VERSION 5.7 ;
  NOWIREEXTENSIONATPIN ON ;
  DIVIDERCHAR "/" ;
  BUSBITCHARS "[]" ;
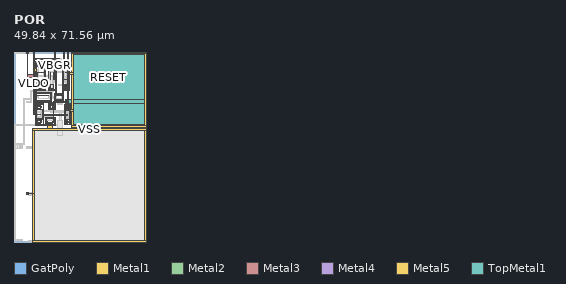
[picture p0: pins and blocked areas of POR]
MACRO POR
  CLASS BLOCK ;
  FOREIGN POR ;
  ORIGIN -315.320 62.220 ;
  SIZE 49.840 BY 71.560 ;
  PIN VLDO
    ANTENNAGATEAREA 5.000000 ;
    ANTENNADIFFAREA 31.500000 ;
    PORT
      LAYER GatPoly ;
        RECT 320.170 8.760 320.670 9.190 ;
        RECT 331.975 6.280 332.475 6.710 ;
        RECT 324.205 3.790 324.385 4.790 ;
        RECT 326.385 4.780 326.565 4.790 ;
        RECT 326.385 3.800 326.755 4.780 ;
        RECT 326.385 3.790 326.565 3.800 ;
        RECT 324.205 -4.130 324.385 -3.130 ;
        RECT 326.385 -3.140 326.565 -3.130 ;
        RECT 326.385 -4.120 326.755 -3.140 ;
        RECT 326.385 -4.130 326.565 -4.120 ;
        RECT 324.160 -11.325 324.340 -11.220 ;
        RECT 323.930 -11.625 324.340 -11.325 ;
        RECT 324.160 -11.720 324.340 -11.625 ;
        RECT 325.340 -11.720 325.520 -11.220 ;
        RECT 324.160 -16.745 324.340 -16.640 ;
        RECT 323.930 -17.045 324.340 -16.745 ;
        RECT 324.160 -17.140 324.340 -17.045 ;
        RECT 325.340 -17.140 325.520 -16.640 ;
      LAYER Metal1 ;
        RECT 320.190 8.910 320.650 9.170 ;
        RECT 331.995 6.665 332.455 6.690 ;
        RECT 331.755 6.455 332.455 6.665 ;
        RECT 331.995 6.430 332.455 6.455 ;
        RECT 323.515 5.590 327.265 5.890 ;
        RECT 323.515 3.130 323.815 5.590 ;
        RECT 324.385 5.060 326.385 5.590 ;
        RECT 324.385 4.900 326.685 5.060 ;
        RECT 326.525 3.680 326.685 4.900 ;
        RECT 324.385 3.520 326.685 3.680 ;
        RECT 322.755 2.020 323.815 3.130 ;
        RECT 320.310 -0.200 320.520 0.910 ;
        RECT 322.755 -0.200 322.965 0.910 ;
        RECT 323.515 -4.910 323.815 2.020 ;
        RECT 324.045 1.630 326.385 1.790 ;
        RECT 324.045 0.910 324.205 1.630 ;
        RECT 323.995 -0.200 324.205 0.910 ;
        RECT 324.045 -0.970 324.205 -0.200 ;
        RECT 324.045 -1.130 326.385 -0.970 ;
        RECT 324.385 -3.020 326.685 -2.860 ;
        RECT 326.525 -4.240 326.685 -3.020 ;
        RECT 324.385 -4.400 326.685 -4.240 ;
        RECT 324.385 -4.910 326.385 -4.400 ;
        RECT 326.965 -4.910 327.265 5.590 ;
        RECT 323.515 -5.210 327.265 -4.910 ;
        RECT 323.515 -5.910 323.815 -5.210 ;
        RECT 323.515 -6.210 329.365 -5.910 ;
        RECT 323.515 -8.960 323.815 -6.210 ;
        RECT 324.435 -6.905 328.005 -6.880 ;
        RECT 324.435 -7.065 328.435 -6.905 ;
        RECT 324.435 -7.090 328.005 -7.065 ;
        RECT 329.065 -8.960 329.365 -6.210 ;
        RECT 323.515 -9.260 329.365 -8.960 ;
        RECT 323.515 -9.960 323.815 -9.260 ;
        RECT 323.515 -10.260 326.565 -9.960 ;
        RECT 323.515 -18.110 323.815 -10.260 ;
        RECT 324.340 -10.950 325.340 -10.260 ;
        RECT 324.000 -11.110 325.340 -10.950 ;
        RECT 324.000 -11.830 324.160 -11.110 ;
        RECT 324.000 -11.990 325.340 -11.830 ;
        RECT 324.435 -14.100 325.135 -14.075 ;
        RECT 324.340 -14.260 325.340 -14.100 ;
        RECT 324.435 -14.285 325.135 -14.260 ;
        RECT 324.000 -16.530 325.340 -16.370 ;
        RECT 324.000 -17.250 324.160 -16.530 ;
        RECT 324.000 -17.410 325.340 -17.250 ;
        RECT 324.340 -18.110 325.340 -17.410 ;
        RECT 326.265 -18.110 326.565 -10.260 ;
        RECT 329.070 -10.705 329.770 -10.680 ;
        RECT 328.925 -10.865 329.925 -10.705 ;
        RECT 329.070 -10.890 329.770 -10.865 ;
        RECT 327.225 -15.760 330.825 -15.460 ;
        RECT 327.225 -18.110 327.525 -15.760 ;
        RECT 330.525 -18.110 330.825 -15.760 ;
        RECT 323.515 -18.410 330.825 -18.110 ;
      LAYER Metal2 ;
        RECT 320.270 -0.200 320.560 9.140 ;
        RECT 322.490 -14.280 322.985 9.340 ;
        RECT 331.755 6.455 332.455 6.665 ;
        RECT 324.000 -0.200 324.200 0.910 ;
        RECT 324.435 -7.085 328.005 -6.885 ;
        RECT 329.070 -10.885 329.770 -9.525 ;
        RECT 324.340 -14.280 325.190 -14.080 ;
      LAYER Metal3 ;
        RECT 322.490 6.415 332.455 6.705 ;
        RECT 322.760 2.020 322.960 3.130 ;
        RECT 320.315 -0.200 324.200 0.910 ;
        RECT 322.490 -7.085 328.005 -6.885 ;
        RECT 322.490 -9.725 329.770 -9.525 ;
        RECT 322.490 -14.280 325.135 -14.080 ;
    END
  END VLDO
  PIN RESET
    ANTENNAGATEAREA 1.500000 ;
    ANTENNADIFFAREA 0.870000 ;
    PORT
      LAYER GatPoly ;
        RECT 328.745 -11.475 328.925 -10.975 ;
        RECT 329.925 -11.070 330.105 -10.975 ;
        RECT 329.925 -11.370 330.360 -11.070 ;
        RECT 329.925 -11.475 330.105 -11.370 ;
        RECT 327.745 -17.185 327.925 -16.685 ;
        RECT 329.925 -16.800 330.105 -16.685 ;
        RECT 329.925 -17.100 330.360 -16.800 ;
        RECT 329.925 -17.185 330.105 -17.100 ;
      LAYER Metal1 ;
        RECT 330.105 -11.475 330.315 -10.975 ;
        RECT 324.340 -12.500 326.035 -12.340 ;
        RECT 325.875 -14.120 326.035 -12.500 ;
        RECT 325.875 -14.410 326.085 -14.120 ;
        RECT 335.190 -14.160 335.400 -14.120 ;
        RECT 335.120 -14.370 335.620 -14.160 ;
        RECT 335.190 -14.410 335.400 -14.370 ;
        RECT 325.875 -15.860 326.035 -14.410 ;
        RECT 324.340 -16.020 326.035 -15.860 ;
        RECT 330.105 -17.185 330.315 -16.685 ;
      LAYER Metal2 ;
        RECT 335.345 -9.045 335.840 9.340 ;
        RECT 325.875 -14.610 326.155 -13.920 ;
        RECT 330.105 -17.185 330.310 -9.440 ;
        RECT 335.275 -9.745 335.885 -9.045 ;
        RECT 335.195 -14.160 335.395 -14.120 ;
        RECT 334.900 -14.370 335.590 -14.160 ;
        RECT 335.195 -14.410 335.395 -14.370 ;
      LAYER Metal3 ;
        RECT 335.275 -9.440 335.885 -9.045 ;
        RECT 330.110 -9.730 335.885 -9.440 ;
        RECT 335.275 -9.745 335.885 -9.730 ;
        RECT 325.880 -14.410 335.400 -14.120 ;
      LAYER Metal4 ;
        RECT 335.275 -9.745 335.885 -9.045 ;
      LAYER Metal5 ;
        RECT 335.270 -9.745 335.890 -9.045 ;
      LAYER TopMetal1 ;
        RECT 337.840 -8.575 364.300 8.390 ;
        RECT 334.760 -10.215 364.300 -8.575 ;
        RECT 337.840 -18.070 364.300 -10.215 ;
    END
  END RESET
  PIN VBGR
    ANTENNAGATEAREA 2.000000 ;
    PORT
      LAYER GatPoly ;
        RECT 328.880 0.520 329.060 1.520 ;
        RECT 330.060 1.340 330.580 1.520 ;
        RECT 330.060 0.700 330.880 1.340 ;
        RECT 330.060 0.520 330.580 0.700 ;
        RECT 328.880 -0.860 329.060 0.140 ;
        RECT 330.060 -0.040 330.580 0.140 ;
        RECT 330.060 -0.680 330.880 -0.040 ;
        RECT 330.060 -0.860 330.580 -0.680 ;
      LAYER Metal1 ;
        RECT 330.625 0.670 330.835 1.370 ;
        RECT 330.625 -0.710 330.835 -0.010 ;
      LAYER Metal2 ;
        RECT 330.630 -0.710 330.830 9.340 ;
    END
  END VBGR
  PIN VSS
    USE GROUND ;
    PORT
      LAYER GatPoly ;
        RECT 328.880 4.780 329.060 4.790 ;
        RECT 328.650 3.800 329.060 4.780 ;
        RECT 328.880 3.790 329.060 3.800 ;
        RECT 330.060 3.790 330.240 4.790 ;
        RECT 334.455 4.780 334.635 4.790 ;
        RECT 334.195 3.800 334.635 4.780 ;
        RECT 334.455 3.790 334.635 3.800 ;
        RECT 335.135 3.790 335.315 4.790 ;
        RECT 328.880 -3.140 329.060 -3.130 ;
        RECT 328.650 -4.120 329.060 -3.140 ;
        RECT 328.880 -4.130 329.060 -4.120 ;
        RECT 330.060 -4.130 330.240 -3.130 ;
        RECT 334.455 -3.140 334.635 -3.130 ;
        RECT 334.195 -4.120 334.635 -3.140 ;
        RECT 334.455 -4.130 334.635 -4.120 ;
        RECT 335.135 -4.130 335.315 -3.130 ;
        RECT 334.940 -11.400 335.120 -11.305 ;
        RECT 334.710 -11.700 335.120 -11.400 ;
        RECT 334.940 -11.805 335.120 -11.700 ;
        RECT 335.620 -11.805 335.800 -11.305 ;
        RECT 334.940 -16.820 335.120 -16.725 ;
        RECT 334.710 -17.120 335.120 -16.820 ;
        RECT 334.940 -17.225 335.120 -17.120 ;
        RECT 335.620 -17.225 335.800 -16.725 ;
        RECT 320.170 -44.190 320.670 -43.760 ;
      LAYER Metal1 ;
        RECT 333.935 5.670 334.430 9.340 ;
        RECT 328.160 5.360 331.360 5.660 ;
        RECT 328.160 -4.740 328.460 5.360 ;
        RECT 329.060 5.060 330.060 5.360 ;
        RECT 328.720 4.900 330.060 5.060 ;
        RECT 328.720 3.680 328.880 4.900 ;
        RECT 328.720 3.520 330.060 3.680 ;
        RECT 328.720 -3.020 330.060 -2.860 ;
        RECT 328.720 -4.240 328.880 -3.020 ;
        RECT 328.720 -4.400 330.060 -4.240 ;
        RECT 329.060 -4.740 330.060 -4.400 ;
        RECT 331.060 -4.740 331.360 5.360 ;
        RECT 328.160 -5.040 331.360 -4.740 ;
        RECT 333.695 5.370 336.295 5.670 ;
        RECT 333.695 -0.970 333.995 5.370 ;
        RECT 334.630 5.060 335.135 5.370 ;
        RECT 334.240 4.900 335.135 5.060 ;
        RECT 334.240 3.680 334.450 4.900 ;
        RECT 334.240 3.520 335.135 3.680 ;
        RECT 334.635 1.630 335.475 1.790 ;
        RECT 335.315 -0.970 335.475 1.630 ;
        RECT 333.695 -1.130 335.475 -0.970 ;
        RECT 333.695 -4.730 333.995 -1.130 ;
        RECT 334.240 -3.020 335.135 -2.860 ;
        RECT 334.240 -4.240 334.450 -3.020 ;
        RECT 334.240 -4.400 335.135 -4.240 ;
        RECT 334.630 -4.730 335.135 -4.400 ;
        RECT 335.995 -4.730 336.295 5.370 ;
        RECT 333.695 -5.030 336.295 -4.730 ;
        RECT 331.060 -6.315 331.365 -5.040 ;
        RECT 333.695 -6.315 334.000 -5.030 ;
        RECT 330.505 -6.615 334.005 -6.315 ;
        RECT 330.505 -8.615 330.805 -6.615 ;
        RECT 331.375 -7.080 333.375 -6.615 ;
        RECT 333.705 -8.615 334.005 -6.615 ;
        RECT 330.505 -8.915 334.005 -8.615 ;
        RECT 330.510 -10.060 330.805 -8.915 ;
        RECT 328.210 -10.360 330.810 -10.060 ;
        RECT 328.210 -12.060 328.510 -10.360 ;
        RECT 330.510 -12.060 330.810 -10.360 ;
        RECT 328.210 -12.360 330.810 -12.060 ;
        RECT 334.290 -10.715 336.540 -10.415 ;
        RECT 327.965 -17.295 329.895 -17.270 ;
        RECT 327.925 -17.455 329.925 -17.295 ;
        RECT 327.965 -17.480 329.895 -17.455 ;
        RECT 334.290 -17.815 334.590 -10.715 ;
        RECT 335.120 -11.035 335.620 -10.715 ;
        RECT 334.775 -11.195 335.620 -11.035 ;
        RECT 334.775 -11.915 334.940 -11.195 ;
        RECT 334.775 -12.075 335.620 -11.915 ;
        RECT 336.240 -12.425 336.540 -10.715 ;
        RECT 335.120 -12.585 336.540 -12.425 ;
        RECT 336.240 -15.945 336.540 -12.585 ;
        RECT 335.120 -16.105 336.540 -15.945 ;
        RECT 334.775 -16.615 335.620 -16.455 ;
        RECT 334.775 -17.335 334.940 -16.615 ;
        RECT 334.775 -17.495 335.620 -17.335 ;
        RECT 335.120 -17.815 335.620 -17.495 ;
        RECT 336.240 -17.815 336.540 -16.105 ;
        RECT 334.290 -18.115 336.540 -17.815 ;
        RECT 320.190 -43.930 320.650 -43.910 ;
        RECT 319.950 -44.140 320.650 -43.930 ;
        RECT 320.190 -44.170 320.650 -44.140 ;
      LAYER Metal2 ;
        RECT 336.055 0.920 336.265 1.620 ;
        RECT 336.305 -13.120 336.515 -12.420 ;
        RECT 327.965 -17.475 329.895 -17.275 ;
        RECT 319.950 -44.140 320.650 -43.930 ;
      LAYER Metal3 ;
        RECT 336.055 0.920 336.265 1.620 ;
        RECT 336.305 -13.120 336.515 -12.420 ;
        RECT 327.965 -17.475 329.895 -17.275 ;
        RECT 319.950 -44.140 320.650 -43.930 ;
      LAYER Metal4 ;
        RECT 336.055 0.920 336.265 1.620 ;
        RECT 336.305 -13.120 336.515 -12.420 ;
        RECT 327.965 -17.475 329.895 -17.275 ;
        RECT 319.950 -44.140 320.650 -43.930 ;
      LAYER Metal5 ;
        RECT 336.980 8.650 365.160 9.250 ;
        RECT 336.980 1.620 337.580 8.650 ;
        RECT 336.040 0.920 337.580 1.620 ;
        RECT 336.980 -12.420 337.580 0.920 ;
        RECT 336.290 -13.120 337.580 -12.420 ;
        RECT 327.965 -19.500 329.895 -17.275 ;
        RECT 336.980 -18.330 337.580 -13.120 ;
        RECT 364.560 -18.330 365.160 8.650 ;
        RECT 336.980 -18.930 365.160 -18.330 ;
        RECT 336.980 -19.500 337.570 -18.930 ;
        RECT 322.440 -20.100 365.160 -19.500 ;
        RECT 322.440 -43.930 323.040 -20.100 ;
        RECT 319.950 -44.140 323.040 -43.930 ;
        RECT 322.440 -61.620 323.040 -44.140 ;
        RECT 364.560 -61.620 365.160 -20.100 ;
        RECT 322.440 -62.220 365.160 -61.620 ;
    END
  END VSS
  OBS
      LAYER GatPoly ;
        RECT 315.350 8.760 315.850 9.190 ;
        RECT 316.030 8.760 316.530 9.190 ;
        RECT 316.745 8.760 317.245 9.190 ;
        RECT 317.445 8.760 317.945 9.190 ;
        RECT 318.145 8.760 318.645 9.190 ;
        RECT 318.850 8.760 319.350 9.190 ;
        RECT 320.870 8.760 321.370 9.190 ;
        RECT 321.570 8.760 322.070 9.190 ;
        RECT 332.655 6.280 333.155 6.710 ;
        RECT 324.205 1.900 324.385 2.900 ;
        RECT 326.385 2.890 326.565 2.900 ;
        RECT 326.385 1.910 326.795 2.890 ;
        RECT 326.385 1.900 326.565 1.910 ;
        RECT 328.880 1.900 329.060 2.900 ;
        RECT 330.060 2.710 330.240 2.900 ;
        RECT 330.060 2.070 330.435 2.710 ;
        RECT 330.060 1.900 330.240 2.070 ;
        RECT 334.455 1.900 334.635 2.900 ;
        RECT 335.135 2.890 335.585 2.900 ;
        RECT 335.135 1.910 335.885 2.890 ;
        RECT 335.135 1.900 335.585 1.910 ;
        RECT 324.205 0.520 324.385 1.520 ;
        RECT 326.385 1.510 326.565 1.520 ;
        RECT 326.385 0.530 326.795 1.510 ;
        RECT 326.385 0.520 326.565 0.530 ;
        RECT 334.455 0.520 334.635 1.520 ;
        RECT 335.135 1.510 335.585 1.520 ;
        RECT 335.135 0.530 335.885 1.510 ;
        RECT 335.135 0.520 335.585 0.530 ;
        RECT 324.205 -0.860 324.385 0.140 ;
        RECT 326.385 0.130 326.565 0.140 ;
        RECT 326.385 -0.850 326.795 0.130 ;
        RECT 326.385 -0.860 326.565 -0.850 ;
        RECT 334.455 -0.860 334.635 0.140 ;
        RECT 335.135 0.130 335.585 0.140 ;
        RECT 335.135 -0.850 335.885 0.130 ;
        RECT 335.135 -0.860 335.585 -0.850 ;
        RECT 324.205 -2.240 324.385 -1.240 ;
        RECT 326.385 -1.250 326.565 -1.240 ;
        RECT 326.385 -2.230 326.795 -1.250 ;
        RECT 326.385 -2.240 326.565 -2.230 ;
        RECT 328.880 -2.240 329.060 -1.240 ;
        RECT 330.060 -1.420 330.240 -1.240 ;
        RECT 330.060 -2.060 330.435 -1.420 ;
        RECT 330.060 -2.240 330.240 -2.060 ;
        RECT 334.455 -2.240 334.635 -1.240 ;
        RECT 335.135 -1.250 335.585 -1.240 ;
        RECT 335.135 -2.230 335.885 -1.250 ;
        RECT 335.135 -2.240 335.585 -2.230 ;
        RECT 331.975 -3.150 332.475 -2.720 ;
        RECT 332.655 -3.150 333.155 -2.720 ;
        RECT 324.255 -7.975 324.435 -7.175 ;
        RECT 328.435 -7.390 328.615 -7.175 ;
        RECT 331.195 -7.390 331.375 -7.190 ;
        RECT 328.435 -7.690 328.805 -7.390 ;
        RECT 330.945 -7.690 331.375 -7.390 ;
        RECT 328.435 -7.975 328.615 -7.690 ;
        RECT 331.195 -7.990 331.375 -7.690 ;
        RECT 333.375 -7.990 333.555 -7.190 ;
        RECT 320.170 -8.470 320.670 -8.040 ;
        RECT 320.870 -8.470 321.370 -8.040 ;
        RECT 321.570 -8.470 322.070 -8.040 ;
        RECT 320.170 -9.600 320.670 -9.170 ;
        RECT 320.870 -9.600 321.370 -9.170 ;
        RECT 321.570 -9.600 322.070 -9.170 ;
        RECT 331.655 -10.460 333.655 -10.030 ;
        RECT 324.160 -13.110 324.340 -12.610 ;
        RECT 325.340 -12.715 325.520 -12.610 ;
        RECT 334.940 -12.715 335.120 -12.695 ;
        RECT 325.340 -13.015 325.715 -12.715 ;
        RECT 334.735 -13.015 335.120 -12.715 ;
        RECT 325.340 -13.110 325.520 -13.015 ;
        RECT 334.940 -13.195 335.120 -13.015 ;
        RECT 335.620 -13.195 335.800 -12.695 ;
        RECT 324.160 -13.990 324.340 -13.490 ;
        RECT 325.340 -13.585 325.520 -13.490 ;
        RECT 325.340 -13.885 325.715 -13.585 ;
        RECT 334.940 -13.675 335.120 -13.575 ;
        RECT 325.340 -13.990 325.520 -13.885 ;
        RECT 334.710 -13.975 335.120 -13.675 ;
        RECT 334.940 -14.075 335.120 -13.975 ;
        RECT 335.620 -14.075 335.800 -13.575 ;
        RECT 324.160 -14.870 324.340 -14.370 ;
        RECT 325.340 -14.465 325.520 -14.370 ;
        RECT 325.340 -14.765 325.715 -14.465 ;
        RECT 334.940 -14.555 335.120 -14.455 ;
        RECT 325.340 -14.870 325.520 -14.765 ;
        RECT 334.710 -14.855 335.120 -14.555 ;
        RECT 334.940 -14.955 335.120 -14.855 ;
        RECT 335.620 -14.955 335.800 -14.455 ;
        RECT 324.160 -15.750 324.340 -15.250 ;
        RECT 325.340 -15.345 325.520 -15.250 ;
        RECT 325.340 -15.645 325.715 -15.345 ;
        RECT 334.940 -15.435 335.120 -15.335 ;
        RECT 325.340 -15.750 325.520 -15.645 ;
        RECT 334.710 -15.735 335.120 -15.435 ;
        RECT 334.940 -15.835 335.120 -15.735 ;
        RECT 335.620 -15.835 335.800 -15.335 ;
        RECT 331.655 -18.340 333.655 -17.910 ;
        RECT 315.350 -25.670 315.850 -25.240 ;
        RECT 316.030 -25.670 316.530 -25.240 ;
        RECT 316.745 -25.670 317.245 -25.240 ;
        RECT 317.445 -25.670 317.945 -25.240 ;
        RECT 318.145 -25.670 318.645 -25.240 ;
        RECT 318.850 -25.670 319.350 -25.240 ;
        RECT 315.350 -27.100 315.850 -26.670 ;
        RECT 316.030 -27.100 316.530 -26.670 ;
        RECT 316.745 -27.100 317.245 -26.670 ;
        RECT 317.445 -27.100 317.945 -26.670 ;
        RECT 318.145 -27.100 318.645 -26.670 ;
        RECT 320.170 -26.960 320.670 -26.400 ;
        RECT 320.870 -26.960 321.370 -26.400 ;
        RECT 321.570 -26.960 322.070 -26.400 ;
        RECT 320.870 -44.190 321.370 -43.760 ;
        RECT 321.570 -44.190 322.070 -43.760 ;
        RECT 320.870 -44.800 321.370 -44.370 ;
        RECT 321.570 -44.800 322.070 -44.370 ;
        RECT 315.350 -61.530 315.850 -61.100 ;
        RECT 316.030 -61.530 316.530 -61.100 ;
        RECT 316.745 -61.530 317.245 -61.100 ;
        RECT 317.445 -61.530 317.945 -61.100 ;
        RECT 318.145 -61.530 318.645 -61.100 ;
        RECT 320.870 -62.030 321.370 -61.600 ;
        RECT 321.570 -62.030 322.070 -61.600 ;
      LAYER Metal1 ;
        RECT 315.370 8.910 316.510 9.170 ;
        RECT 316.765 8.910 317.925 9.170 ;
        RECT 318.165 8.910 319.330 9.170 ;
        RECT 320.890 8.910 322.050 9.170 ;
        RECT 332.675 6.430 333.135 6.690 ;
        RECT 324.455 3.170 326.385 3.195 ;
        RECT 329.150 3.170 329.850 3.195 ;
        RECT 334.435 3.170 335.135 3.195 ;
        RECT 324.385 3.010 326.725 3.170 ;
        RECT 324.455 2.985 326.385 3.010 ;
        RECT 324.455 0.410 326.385 0.435 ;
        RECT 324.385 0.250 326.385 0.410 ;
        RECT 324.455 0.225 326.385 0.250 ;
        RECT 326.565 -2.350 326.725 3.010 ;
        RECT 324.385 -2.510 326.725 -2.350 ;
        RECT 328.720 3.010 330.060 3.170 ;
        RECT 334.435 3.010 335.815 3.170 ;
        RECT 328.720 -2.350 328.880 3.010 ;
        RECT 329.150 2.985 329.850 3.010 ;
        RECT 334.435 2.985 335.135 3.010 ;
        RECT 330.180 2.040 330.390 2.740 ;
        RECT 329.150 1.790 329.850 1.815 ;
        RECT 329.060 1.630 330.435 1.790 ;
        RECT 329.150 1.605 329.850 1.630 ;
        RECT 329.150 0.410 329.850 0.435 ;
        RECT 329.060 0.250 330.060 0.410 ;
        RECT 329.150 0.225 329.850 0.250 ;
        RECT 330.275 -0.970 330.435 1.630 ;
        RECT 334.435 0.225 335.135 0.435 ;
        RECT 329.060 -1.130 330.435 -0.970 ;
        RECT 330.180 -2.090 330.390 -1.390 ;
        RECT 335.655 -2.350 335.815 3.010 ;
        RECT 328.720 -2.510 330.060 -2.350 ;
        RECT 334.635 -2.510 335.815 -2.350 ;
        RECT 331.995 -3.130 333.135 -2.870 ;
        RECT 328.505 -7.690 328.805 -7.390 ;
        RECT 330.990 -7.720 331.245 -7.360 ;
        RECT 324.435 -8.085 328.005 -8.075 ;
        RECT 320.190 -8.450 321.350 -8.190 ;
        RECT 320.190 -9.450 321.350 -9.190 ;
        RECT 321.590 -9.450 322.050 -8.190 ;
        RECT 324.435 -8.245 328.435 -8.085 ;
        RECT 331.645 -8.100 333.165 -8.075 ;
        RECT 324.435 -8.285 328.005 -8.245 ;
        RECT 331.375 -8.260 333.375 -8.100 ;
        RECT 331.645 -8.285 333.165 -8.260 ;
        RECT 331.675 -10.330 333.635 -10.030 ;
        RECT 329.075 -11.585 329.775 -11.570 ;
        RECT 328.925 -11.745 329.925 -11.585 ;
        RECT 329.075 -11.780 329.775 -11.745 ;
        RECT 325.440 -13.050 325.695 -12.680 ;
        RECT 334.780 -13.010 334.990 -12.720 ;
        RECT 324.000 -13.380 325.340 -13.220 ;
        RECT 324.000 -14.980 324.160 -13.380 ;
        RECT 325.440 -13.920 325.695 -13.550 ;
        RECT 325.440 -14.800 325.695 -14.430 ;
        RECT 324.435 -14.980 325.135 -14.955 ;
        RECT 324.000 -15.140 325.340 -14.980 ;
        RECT 324.435 -15.165 325.135 -15.140 ;
        RECT 325.440 -15.680 325.695 -15.310 ;
        RECT 334.780 -15.715 334.940 -13.010 ;
        RECT 335.190 -13.280 335.400 -13.240 ;
        RECT 335.120 -13.305 335.620 -13.280 ;
        RECT 335.120 -13.465 335.960 -13.305 ;
        RECT 335.120 -13.490 335.620 -13.465 ;
        RECT 335.190 -13.530 335.400 -13.490 ;
        RECT 335.800 -15.065 335.960 -13.465 ;
        RECT 335.120 -15.225 335.960 -15.065 ;
        RECT 328.170 -16.415 329.690 -16.390 ;
        RECT 327.925 -16.575 329.925 -16.415 ;
        RECT 328.170 -16.600 329.690 -16.575 ;
        RECT 331.675 -18.340 333.635 -18.040 ;
        RECT 315.370 -26.950 315.830 -25.390 ;
        RECT 316.050 -26.950 316.510 -25.390 ;
        RECT 316.765 -26.950 317.225 -25.390 ;
        RECT 317.465 -26.950 317.925 -25.390 ;
        RECT 318.165 -26.950 318.625 -25.390 ;
        RECT 318.870 -25.650 319.330 -25.390 ;
        RECT 320.190 -26.810 320.650 -26.550 ;
        RECT 320.890 -26.810 321.350 -26.550 ;
        RECT 321.590 -26.810 322.050 -26.550 ;
        RECT 320.890 -44.650 321.350 -43.910 ;
        RECT 321.590 -44.650 322.050 -43.910 ;
        RECT 315.370 -61.510 315.830 -61.250 ;
        RECT 316.050 -61.510 317.230 -61.250 ;
        RECT 317.465 -61.510 318.630 -61.250 ;
        RECT 320.890 -61.905 322.050 -61.645 ;
        RECT 320.890 -62.010 321.350 -61.905 ;
        RECT 321.590 -62.010 322.050 -61.905 ;
      LAYER Metal2 ;
        RECT 324.455 2.990 326.385 3.190 ;
        RECT 329.060 2.990 329.850 3.190 ;
        RECT 332.745 2.990 333.035 6.660 ;
        RECT 334.435 2.985 335.135 3.195 ;
        RECT 329.150 1.605 329.850 1.815 ;
        RECT 324.455 0.230 326.385 0.430 ;
        RECT 329.060 0.230 329.850 0.430 ;
        RECT 321.675 -8.220 321.965 -5.280 ;
        RECT 328.550 -7.925 328.760 -7.225 ;
        RECT 329.150 -7.595 329.850 0.230 ;
        RECT 330.185 -5.570 330.385 2.740 ;
        RECT 334.435 0.225 335.135 1.810 ;
        RECT 330.990 -7.945 331.200 -7.245 ;
        RECT 331.675 -8.080 333.190 -8.075 ;
        RECT 319.005 -8.420 321.965 -8.220 ;
        RECT 324.435 -8.280 328.005 -8.080 ;
        RECT 331.645 -8.280 333.190 -8.080 ;
        RECT 315.455 -61.485 315.745 -18.025 ;
        RECT 319.005 -25.620 319.295 -8.420 ;
        RECT 331.675 -10.080 333.190 -8.280 ;
        RECT 331.675 -10.280 333.620 -10.080 ;
        RECT 324.340 -15.160 325.190 -14.960 ;
        RECT 325.465 -15.640 325.665 -12.710 ;
        RECT 329.075 -13.530 329.775 -11.575 ;
        RECT 328.015 -14.965 329.845 -14.960 ;
        RECT 327.965 -15.165 329.895 -14.965 ;
        RECT 328.015 -16.595 329.845 -15.165 ;
        RECT 332.330 -17.335 333.040 -12.765 ;
        RECT 334.415 -13.010 334.985 -12.720 ;
        RECT 335.195 -13.280 335.395 -13.240 ;
        RECT 334.900 -13.490 335.590 -13.280 ;
        RECT 335.195 -13.530 335.395 -13.490 ;
        RECT 332.135 -17.535 333.245 -17.335 ;
        RECT 332.330 -18.085 333.040 -17.535 ;
        RECT 332.325 -18.280 333.040 -18.085 ;
        RECT 332.325 -18.285 333.025 -18.280 ;
      LAYER Metal3 ;
        RECT 324.455 2.990 329.850 3.190 ;
        RECT 332.745 2.990 335.135 3.190 ;
        RECT 329.150 1.610 335.135 1.810 ;
        RECT 324.455 0.230 329.850 0.430 ;
        RECT 321.715 -5.570 330.385 -5.280 ;
        RECT 328.550 -7.690 331.195 -7.390 ;
        RECT 324.435 -8.280 333.190 -8.080 ;
        RECT 325.465 -13.010 334.985 -12.720 ;
        RECT 329.075 -13.530 335.395 -13.240 ;
        RECT 324.435 -15.160 329.895 -14.960 ;
        RECT 327.965 -15.165 329.895 -15.160 ;
        RECT 332.135 -17.535 333.245 -17.335 ;
        RECT 315.495 -18.090 315.695 -18.045 ;
        RECT 332.330 -18.085 333.030 -18.030 ;
        RECT 332.325 -18.090 333.030 -18.085 ;
        RECT 315.320 -18.290 333.400 -18.090 ;
        RECT 315.495 -18.335 315.695 -18.290 ;
      LAYER Metal4 ;
        RECT 332.135 -17.535 333.245 -17.335 ;
      LAYER Metal5 ;
        RECT 332.135 -17.745 333.245 -17.125 ;
      LAYER TopMetal1 ;
        RECT 331.740 -18.385 333.640 -16.485 ;
        RECT 323.010 -61.650 364.590 -20.070 ;
      LAYER TopMetal2 ;
        RECT 331.690 -22.020 333.690 -16.435 ;
  END
END POR
END LIBRARY

